One B-rep face of a CAD part: STEP entity #109.
In plain terms, the planar face has unit normal (-1, 0, 0).
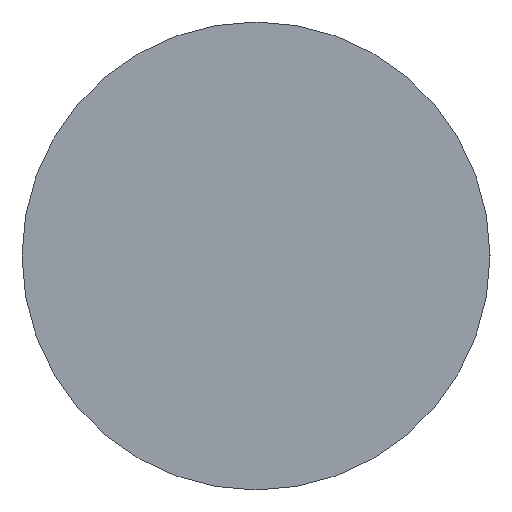
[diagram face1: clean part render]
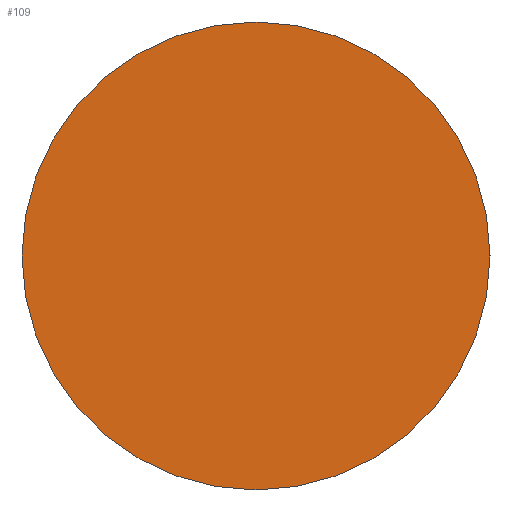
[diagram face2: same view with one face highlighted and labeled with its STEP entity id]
Its self-contained STEP definition (entity closure, numbers rounded to 3 decimals):
#43 = CYLINDRICAL_SURFACE('',#44,1.5);
#44 = AXIS2_PLACEMENT_3D('',#45,#46,#47);
#45 = CARTESIAN_POINT('',(17.,0.,0.));
#46 = DIRECTION('',(-1.,-0.,-0.));
#47 = DIRECTION('',(0.,1.,0.));
#60 = VERTEX_POINT('',#61);
#61 = CARTESIAN_POINT('',(0.,1.5,0.));
#82 = EDGE_CURVE('',#60,#60,#83,.T.);
#83 = SURFACE_CURVE('',#84,(#89,#96),.PCURVE_S1.);
#84 = CIRCLE('',#85,1.5);
#85 = AXIS2_PLACEMENT_3D('',#86,#87,#88);
#86 = CARTESIAN_POINT('',(0.,0.,0.));
#87 = DIRECTION('',(1.,0.,0.));
#88 = DIRECTION('',(-0.,1.,0.));
#89 = PCURVE('',#43,#90);
#90 = DEFINITIONAL_REPRESENTATION('',(#91),#95);
#91 = LINE('',#92,#93);
#92 = CARTESIAN_POINT('',(-0.,17.));
#93 = VECTOR('',#94,1.);
#94 = DIRECTION('',(-1.,0.));
#95 = ( GEOMETRIC_REPRESENTATION_CONTEXT(2) 
PARAMETRIC_REPRESENTATION_CONTEXT() REPRESENTATION_CONTEXT('2D SPACE',''
  ) );
#96 = PCURVE('',#97,#102);
#97 = PLANE('',#98);
#98 = AXIS2_PLACEMENT_3D('',#99,#100,#101);
#99 = CARTESIAN_POINT('',(0.,0.,0.));
#100 = DIRECTION('',(1.,0.,0.));
#101 = DIRECTION('',(-0.,1.,0.));
#102 = DEFINITIONAL_REPRESENTATION('',(#103),#107);
#103 = CIRCLE('',#104,1.5);
#104 = AXIS2_PLACEMENT_2D('',#105,#106);
#105 = CARTESIAN_POINT('',(0.,0.));
#106 = DIRECTION('',(1.,0.));
#107 = ( GEOMETRIC_REPRESENTATION_CONTEXT(2) 
PARAMETRIC_REPRESENTATION_CONTEXT() REPRESENTATION_CONTEXT('2D SPACE',''
  ) );
#109 = ADVANCED_FACE('',(#110),#97,.F.);
#110 = FACE_BOUND('',#111,.F.);
#111 = EDGE_LOOP('',(#112));
#112 = ORIENTED_EDGE('',*,*,#82,.T.);
